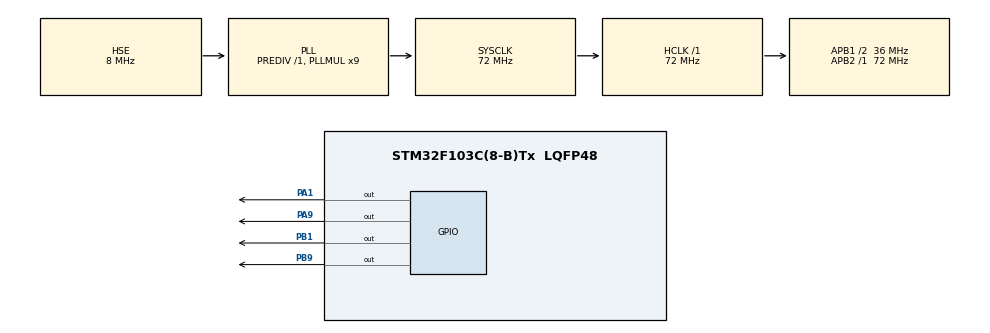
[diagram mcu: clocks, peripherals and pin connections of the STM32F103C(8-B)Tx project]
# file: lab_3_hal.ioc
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FREERTOS.Tasks01=defaultTask,24,128,StartDefaultTask,Default,NULL,Dynamic,NULL,NULL
Mcu.Family=STM32F1
Mcu.Name=STM32F103C(8-B)Tx
Mcu.Package=LQFP48
NVIC.PriorityGroup=NVIC_PRIORITYGROUP_4
NVIC.TIM1_UP_IRQn=true\:0\:0\:false\:false\:true\:false\:false\:true
NVIC.TIM2_IRQn=true\:5\:0\:false\:false\:true\:false\:true\:true
NVIC.TimeBase=TIM1_UP_IRQn
NVIC.TimeBaseIP=TIM1
PA1.Signal=GPIO_Output
PA13.Mode=Serial_Wire
PA13.Signal=SYS_JTMS-SWDIO
PA14.Mode=Serial_Wire
PA14.Signal=SYS_JTCK-SWCLK
PA9.Signal=GPIO_Output
PB1.Signal=GPIO_Output
PB9.Signal=GPIO_Output
PD0-OSC_IN.Mode=HSE-External-Oscillator
PD0-OSC_IN.Signal=RCC_OSC_IN
PD1-OSC_OUT.Mode=HSE-External-Oscillator
PD1-OSC_OUT.Signal=RCC_OSC_OUT
ProjectManager.HeapSize=0x200
ProjectManager.StackSize=0x400
ProjectManager.TargetToolchain=MDK-ARM V5.27
RCC.AHBFreq_Value=72000000
RCC.APB1CLKDivider=RCC_HCLK_DIV2
RCC.APB1Freq_Value=36000000
RCC.APB1TimFreq_Value=72000000
RCC.APB2Freq_Value=72000000
RCC.APB2TimFreq_Value=72000000
RCC.HCLKFreq_Value=72000000
RCC.PLLMUL=RCC_PLL_MUL9
RCC.PLLSourceVirtual=RCC_PLLSOURCE_HSE
RCC.SYSCLKFreq_VALUE=72000000
RCC.SYSCLKSource=RCC_SYSCLKSOURCE_PLLCLK
RCC.USBFreq_Value=72000000
TIM2.Period=9
VP_FREERTOS_VS_CMSIS_V2.Mode=CMSIS_V2
VP_SYS_VS_tim1.Mode=TIM1
VP_TIM2_VS_ClockSourceINT.Mode=Internal
board=custom

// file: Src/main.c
/*Yukhymchuk Anastasiia IT-81, RTOS, Lab 1*/
/* USER CODE BEGIN Header */
/**
  ******************************************************************************
  * @file           : main.c
  * @brief          : Main program body
  ******************************************************************************
  * @attention
  *
  * <h2><center>&copy; Copyright (c) 2021 STMicroelectronics.
  * All rights reserved.</center></h2>
  *
  * This software component is licensed by ST under Ultimate Liberty license
  * SLA0044, the "License"; You may not use this file except in compliance with
  * the License. You may obtain a copy of the License at:
  *                             www.st.com/SLA0044
  *
  ******************************************************************************
  */
/* USER CODE END Header */

#include "main.h"
#include "cmsis_os.h"

TIM_HandleTypeDef htim2;
volatile uint32_t ticks_delay;

void SystemClock_Config(void);
static void MX_GPIO_Init(void);
static void MX_TIM2_Init(void);

/* 2 counters for timers*/
volatile uint16_t counter1 = 0;
volatile uint16_t counter2 = 0;

/* 2 handlers for threads*/
osThreadId_t ThreadId1;
osThreadId_t ThreadId2;
/* 2 handlers for timers*/
osTimerId_t TimerId1;
osTimerId_t TimerId2;

/* virtual timer 1 and 2  callback */
void timerCallback(void *argument);

/* thread function */
void pwmThreadFunc(void *param);

void _delay_ms(uint32_t ms);
void initGPIO(void);
void PWM(uint16_t dutyCycle, uint16_t period, GPIO_TypeDef* port, uint16_t pin);

const osThreadAttr_t thread1_attr = {
  .priority = osPriorityAboveNormal                   //Set initial thread priority to above normal
};

int main(void)
{

  /* MCU Configuration--------------------------------------------------------*/

  /* Reset of all peripherals, Initializes the Flash interface and the Systick. */
  HAL_Init();

  /* Configure the system clock */
  SystemClock_Config();

  /* Initialize all configured peripherals */
  MX_GPIO_Init();
  MX_TIM2_Init();

  /* Init scheduler */
  osKernelInitialize();

  /* USER CODE BEGIN RTOS_THREADS */

		ThreadId1 = osThreadNew(pwmThreadFunc, GPIOA,&thread1_attr);
	  ThreadId2 = osThreadNew(pwmThreadFunc, GPIOB, NULL);

	  TimerId1 = osTimerNew(timerCallback, osTimerPeriodic, GPIOA, NULL);
	  TimerId2 = osTimerNew(timerCallback, osTimerPeriodic, GPIOB, NULL);

	  osTimerStart(TimerId1, 15U);
	  osTimerStart(TimerId2, 15U);
  /* USER CODE END RTOS_THREADS */

  /* Start scheduler */
  osKernelStart();

  /* We should never get here as control is now taken by the scheduler */
  /* Infinite loop */
  /* USER CODE BEGIN WHILE */
  while (1)
  {

  }
  /* USER CODE END 3 */
}

void _delay_ms(uint32_t ms)
{
	uint32_t start = ticks_delay;
  while((ticks_delay - start) < ms);
}

void PWM(uint16_t dutyCycle, uint16_t period, GPIO_TypeDef* port, uint16_t pin)
{
	HAL_GPIO_WritePin(port, pin, GPIO_PIN_SET);
	_delay_ms(dutyCycle);
	HAL_GPIO_WritePin(port, pin, GPIO_PIN_RESET);
	_delay_ms(period - dutyCycle);
}

void pwmThreadFunc(void* argument)
{
	while(1){
		PWM(15, 30, argument, GPIO_PIN_0);
	}
}

void timerCallback(void *argument)
{
	HAL_GPIO_TogglePin(argument, GPIO_PIN_8);
}

void SystemClock_Config(void)
{
  RCC_OscInitTypeDef RCC_OscInitStruct = {0};
  RCC_ClkInitTypeDef RCC_ClkInitStruct = {0};

  /** Initializes the CPU, AHB and APB busses clocks
  */
  RCC_OscInitStruct.OscillatorType = RCC_OSCILLATORTYPE_HSE;
  RCC_OscInitStruct.HSEState = RCC_HSE_ON;
  RCC_OscInitStruct.HSEPredivValue = RCC_HSE_PREDIV_DIV1;
  RCC_OscInitStruct.HSIState = RCC_HSI_ON;
  RCC_OscInitStruct.PLL.PLLState = RCC_PLL_ON;
  RCC_OscInitStruct.PLL.PLLSource = RCC_PLLSOURCE_HSE;
  RCC_OscInitStruct.PLL.PLLMUL = RCC_PLL_MUL9;
  if (HAL_RCC_OscConfig(&RCC_OscInitStruct) != HAL_OK)
  {
    Error_Handler();
  }
  /** Initializes the CPU, AHB and APB busses clocks
  */
  RCC_ClkInitStruct.ClockType = RCC_CLOCKTYPE_HCLK|RCC_CLOCKTYPE_SYSCLK
                              |RCC_CLOCKTYPE_PCLK1|RCC_CLOCKTYPE_PCLK2;
  RCC_ClkInitStruct.SYSCLKSource = RCC_SYSCLKSOURCE_PLLCLK;
  RCC_ClkInitStruct.AHBCLKDivider = RCC_SYSCLK_DIV1;
  RCC_ClkInitStruct.APB1CLKDivider = RCC_HCLK_DIV2;
  RCC_ClkInitStruct.APB2CLKDivider = RCC_HCLK_DIV1;

  if (HAL_RCC_ClockConfig(&RCC_ClkInitStruct, FLASH_LATENCY_2) != HAL_OK)
  {
    Error_Handler();
  }
}

static void MX_TIM2_Init(void)
{

  TIM_ClockConfigTypeDef sClockSourceConfig = {0};
  TIM_MasterConfigTypeDef sMasterConfig = {0};

  htim2.Instance = TIM2;
  htim2.Init.Prescaler = SystemCoreClock/10000U - 1;
  htim2.Init.CounterMode = TIM_COUNTERMODE_UP;
  htim2.Init.Period = 9;
  htim2.Init.ClockDivision = TIM_CLOCKDIVISION_DIV1;
  htim2.Init.AutoReloadPreload = TIM_AUTORELOAD_PRELOAD_DISABLE;
  if (HAL_TIM_Base_Init(&htim2) != HAL_OK)
  {
    Error_Handler();
  }
  sClockSourceConfig.ClockSource = TIM_CLOCKSOURCE_INTERNAL;
  if (HAL_TIM_ConfigClockSource(&htim2, &sClockSourceConfig) != HAL_OK)
  {
    Error_Handler();
  }
  sMasterConfig.MasterOutputTrigger = TIM_TRGO_RESET;
  sMasterConfig.MasterSlaveMode = TIM_MASTERSLAVEMODE_DISABLE;
  if (HAL_TIMEx_MasterConfigSynchronization(&htim2, &sMasterConfig) != HAL_OK)
  {
    Error_Handler();
  }
  /* USER CODE BEGIN TIM2_Init 2 */
	HAL_TIM_Base_Start_IT(&htim2);
  /* USER CODE END TIM2_Init 2 */

}

static void MX_GPIO_Init(void)
{
  GPIO_InitTypeDef GPIO_InitStruct = {0};

  /* GPIO Ports Clock Enable */
  __HAL_RCC_GPIOD_CLK_ENABLE();
  __HAL_RCC_GPIOA_CLK_ENABLE();
  __HAL_RCC_GPIOB_CLK_ENABLE();

  /*Configure GPIO pin Output Level */
  HAL_GPIO_WritePin(GPIOA, GPIO_PIN_0|GPIO_PIN_8, GPIO_PIN_RESET);

  /*Configure GPIO pin Output Level */
  HAL_GPIO_WritePin(GPIOB, GPIO_PIN_0|GPIO_PIN_8, GPIO_PIN_RESET);

  /*Configure GPIO pins : PA0 PA8 */
  GPIO_InitStruct.Pin = GPIO_PIN_0|GPIO_PIN_8;
  GPIO_InitStruct.Mode = GPIO_MODE_OUTPUT_PP;
  GPIO_InitStruct.Pull = GPIO_NOPULL;
  GPIO_InitStruct.Speed = GPIO_SPEED_FREQ_LOW;
  HAL_GPIO_Init(GPIOA, &GPIO_InitStruct);

  /*Configure GPIO pins : PB0 PB8 */
  GPIO_InitStruct.Pin = GPIO_PIN_0|GPIO_PIN_8;
  GPIO_InitStruct.Mode = GPIO_MODE_OUTPUT_PP;
  GPIO_InitStruct.Pull = GPIO_NOPULL;
  GPIO_InitStruct.Speed = GPIO_SPEED_FREQ_LOW;
  HAL_GPIO_Init(GPIOB, &GPIO_InitStruct);

}

 /**
  * @brief  Period elapsed callback in non blocking mode
  * @note   This function is called  when TIM1 interrupt took place, inside
  * HAL_TIM_IRQHandler(). It makes a direct call to HAL_IncTick() to increment
  * a global variable "uwTick" used as application time base.
  * @param  htim : TIM handle
  * @retval None
  */
void HAL_TIM_PeriodElapsedCallback(TIM_HandleTypeDef *htim)
{
  if (htim->Instance == TIM1) {
    HAL_IncTick();
  }
}

/**
  * @brief This function handles TIM2 global interrupt.
  */
void TIM2_IRQHandler(void)
{
  /* USER CODE BEGIN TIM2_IRQn 0 */
	++ticks_delay;                    //increment counter
  /* USER CODE END TIM2_IRQn 0 */
  HAL_TIM_IRQHandler(&htim2);       //pass htim2 address to handler
}

void Error_Handler(void)
{
}

/************************ (C) COPYRIGHT STMicroelectronics *****END OF FILE****/
